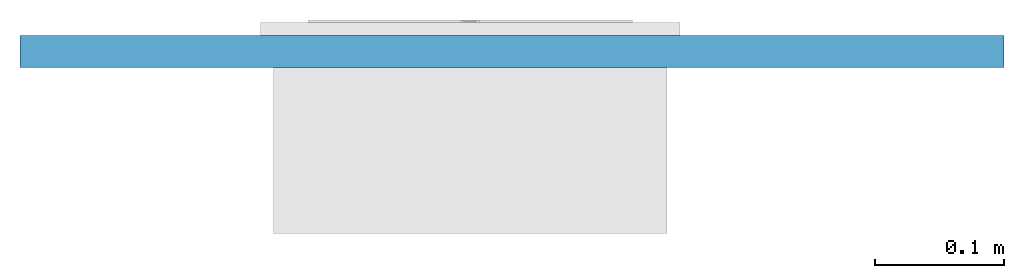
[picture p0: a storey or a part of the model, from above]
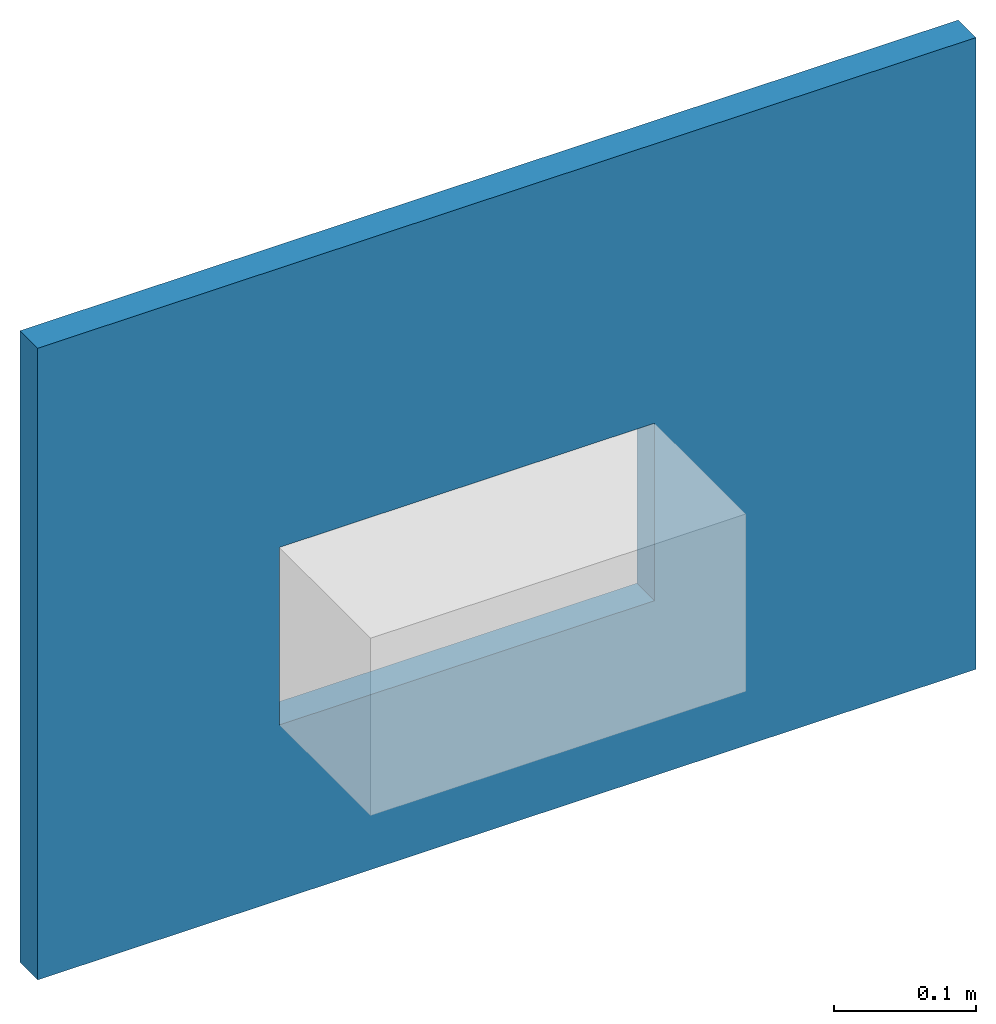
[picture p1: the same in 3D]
Properties of the parts of a building model (IFC2X3)

# File
Description: ViewDefinition [CoordinationView]
Time: 2015-09-10T14:35:47
Written by: The EXPRESS Data Manager Version 5.01.0100.02.64mod : 6 Jun 2012
Made in: 20140709_2115(x64) - Exporter 2014.0.2014.0709 - Default UI
Comment: STEP Physical File produced by: The EXPRESS Data Manager Version 5.01.0100.02.64mod : 6 Jun 2012 * Module: EDMstepFileFactory/EDMstandAlone * Creation date: Thu Sep 10 14:35:47 2015 * Host: BIM-HP * Database: C:\Users\dcole\AppData\Local\Temp\{A5A9EBFE-1901-45B1-A975-F0C54752FEB4}\ifc * Database version: 5507 * Database creation date: Thu Sep 10 14:35:44 2015 * Schema: IFC2X3 * Model: DataRepository.ifc * Model creation date: Thu Sep 10 14:35:46 2015 * Header model: DataRepository.ifc_HeaderModel * Header model creation date: Thu Sep 10 14:35:46 2015 * EDMuser: sdai-user * EDMgroup: sdai-group * License ID and type: 5605 : Permanent license. Expiry date: * EDMstepFileFactory options: 020000

# IfcProject
LongName: C:\Users\dcole\Desktop\Bell_chem\53721_BELL-CHEM\BIM Images 2015\DP3601.ifc

# IfcSite, Default
RefLatitude: 42, 24, 53, 508911; RefLongitude: -71, -15, -29, -58837; RefElevation: 0 mm

# IfcBuilding
Pset_BuildingCommon - NumberOfStoreys: 1

# IfcBuildingStorey, Level 1
LongName: Level 1; Elevation: 0 mm
Graphics - Line Pattern: -3000010; Line Weight: 1; Symbol at End 2 Default: yes; Color: 0; Symbol at End 1 Default: no
Identity Data - Building Story: yes; Name: Level 1; Structural: no
Dimensions - Computation Height: 0 mm
Constraints - Elevation: 0 mm; Elevation Base: Project Base Point

# IfcBuildingElementProxy: DP3601 Dolphin Prestige Under Counter Paper Towel Dispenser, DP3601:DP3601 Dolphin Prestige Under Counter Paper Towel Dispenser:12964
In: Level 1
Material: Stainless Steel
Phasing - Phase Created: New Construction
Constraints - Level: Level: Level 1; Elevation: -126.515 mm
Dimensions - Volume: 0.000811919 m3; Projection: 10mm; Width: 326mm; Capacity Paper Towels: 250 Paper Towels; Height: 173mm; Recess: H155 x W 308mm
Pset_ManufacturerTypeInformation - Manufacturer: Bell-Chem Products Co.
Pset_BuildingElementProxyCommon - Reference: DP3601 Dolphin Prestige Under Counter Paper Towel Dispenser
Identity Data - Description: Under Counter Paper Towel Dispenser; Model: DP 3601; Email: info@dolphindispensers.co.uk; Fax No.: +44 (0) 1424 205200; Tel No.: +44 (0) 1424 202224; Assembly Code: D2010900; Manufacturer: Bell-Chem Products Co.; Assembly Description: Other Plumbing Fixtures; URL: www.dolphindispensers.co.uk; Address line 1: Southpoint, Compass Park, Bodiam, Robertsbridge, TN32 5BS
General - Product Page Link: http://www.dolphindispensers.co.uk/products/dp3601-dolphin-prestige-under-counter-paper-towel-dispenser/109.htm; Product Data: Superior quality and timeless design for prestigious washrooms. Easy-care 18/10 stainless steel. Satin finish, welded corners – no sharp edges. Lockable. The built-in spring mechanism functions with the same force until the last towel has been used. Also available in polished stainless steel or plastic powder coated to a colour of your choice

# IfcOpeningElement: Opening
In: Level 1
Dimensions - Volume: 0.00924437 m3; Length: 765 mm; Area: 0.369775 m2
Constraints - Room Bounding: yes; Top Offset: 0 mm; Location Line: Wall Centerline; Top Extension Distance: 0 mm; Base Constraint: Level: Level 1; Base Offset: -277.372 mm; Base is Attached: no; Base Extension Distance: 0 mm; Related to Mass: no; Unconnected Height: 544.566 mm; Top is Attached: no
Phasing - Phase Created: New Construction
Structural - Enable Analytical Model: no; Structural: no; Structural Usage: Non-bearing
Analytical Properties - Roughness: 1; Absorptance: 0.1
Construction - Width: 25 mm; Function: Exterior; Wrapping at Inserts: Do not wrap
Graphics - Coarse Scale Fill Color: 8454143

# IfcWallStandardCase: Basic Wall:Wall 1, Basic Wall:Wall 1:3092
In: Level 1
Type - PredefinedType: STANDARD; Material: Default Wall 25 mm
Type - Analytical Properties - Roughness: 1; Absorptance: 0.1
Type - Construction - Width: 25 mm; Function: Exterior; Wrapping at Inserts: Do not wrap
Type - Graphics - Coarse Scale Fill Color: 8454143
Dimensions - Volume: 0.00924437 m3; Length: 765 mm; Area: 0.369775 m2
Constraints - Room Bounding: yes; Top Offset: 0 mm; Location Line: Wall Centerline; Top Extension Distance: 0 mm; Base Constraint: Level: Level 1; Base Offset: -277.372 mm; Base is Attached: no; Base Extension Distance: 0 mm; Related to Mass: no; Unconnected Height: 544.566 mm; Top is Attached: no
Phasing - Phase Created: New Construction
Structural - Enable Analytical Model: no; Structural: no; Structural Usage: Non-bearing
Pset_WallCommon - Reference: Wall 1; LoadBearing: no; ExtendToStructure: no; IsExternal: yes
